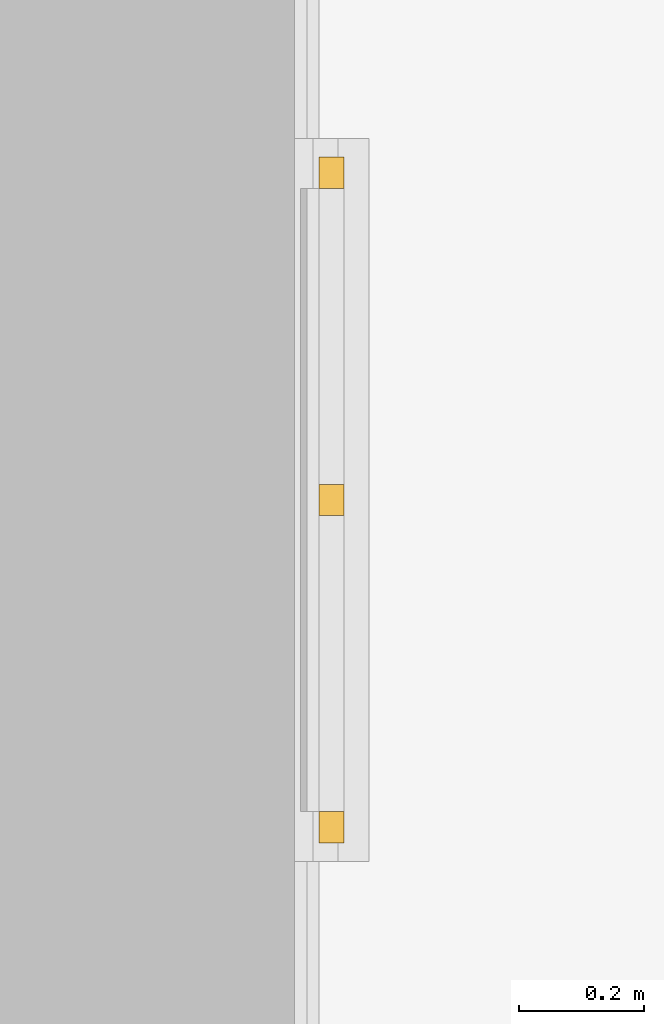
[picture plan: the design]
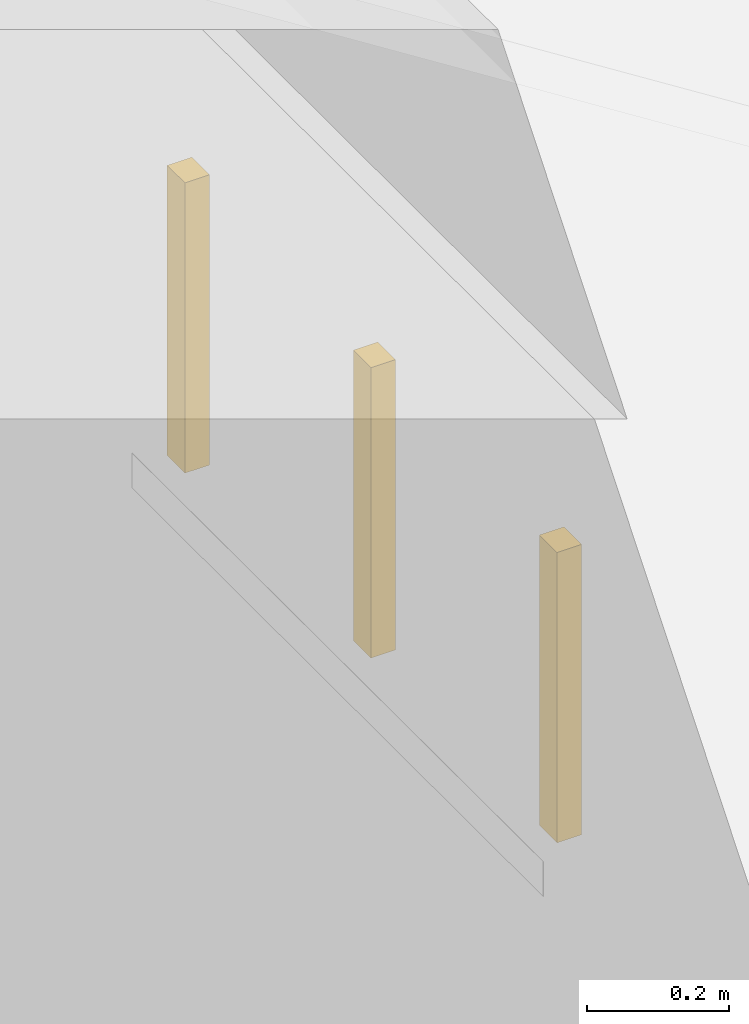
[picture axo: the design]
# One storey, part 86 of 151: 3 windows.
"""IFC2X3 building model written with IfcOpenShell, lengths in metres."""

from ifc_helpers import new_model, si_unit, origin, origin_with_axes, place, context, subcontext, project, spatial, faceted_brep, element, save


model = new_model("IFC2X3")

# Units and contexts
model_context = context("Model", 3, precision=1e-05, world=origin_with_axes())
body_context = subcontext(model_context, "Body", "Model", "MODEL_VIEW")
ifc_project = project(units=[si_unit("LENGTHUNIT", "METRE"), si_unit("AREAUNIT", "SQUARE_METRE"), si_unit("VOLUMEUNIT", "CUBIC_METRE"), si_unit("PLANEANGLEUNIT", "RADIAN")], contexts=[model_context])

# Site, building, storey
site_placement = place(None, origin_with_axes())
site = spatial("IfcSite", under=ifc_project, at=site_placement, CompositionType="ELEMENT")
building_placement = place(site_placement, origin())
building = spatial("IfcBuilding", under=site, at=building_placement, Name="de Temporal", CompositionType="ELEMENT")
storey_placement = place(building_placement, origin())
storey = spatial("IfcBuildingStorey", under=building, at=storey_placement, Name="NIVEL 1 (NPT +0.00)", CompositionType="ELEMENT", Elevation=0.0)

# Windows
window_1_placement = place(storey_placement, origin())
element("IfcWindow", 1, at=window_1_placement, inside=storey, ObjectType="Ventana", context=body_context, shape_type="Brep", body=[
    faceted_brep([(66.54, 118.475, 2.45), (66.54, 118.525, 2.45), (66.58, 118.525, 2.45), (66.58, 118.475, 2.45), (66.54, 118.475, 2.95), (66.58, 118.475, 2.95), (66.58, 118.525, 2.95), (66.54, 118.525, 2.95)], [[[0, 1, 2, 3]], [[4, 5, 6, 7]], [[0, 3, 5, 4]], [[3, 2, 6, 5]], [[2, 1, 7, 6]], [[1, 0, 4, 7]]]),
])
window_2_placement = place(storey_placement, origin())
element("IfcWindow", 2, at=window_2_placement, inside=storey, ObjectType="Ventana", context=body_context, shape_type="Brep", body=[
    faceted_brep([(66.54, 119.525, 2.45), (66.54, 119.575, 2.45), (66.58, 119.575, 2.45), (66.58, 119.525, 2.45), (66.54, 119.525, 2.95), (66.58, 119.525, 2.95), (66.58, 119.575, 2.95), (66.54, 119.575, 2.95)], [[[0, 1, 2, 3]], [[4, 5, 6, 7]], [[0, 3, 5, 4]], [[3, 2, 6, 5]], [[2, 1, 7, 6]], [[1, 0, 4, 7]]]),
])
window_3_placement = place(storey_placement, origin())
element("IfcWindow", 3, at=window_3_placement, inside=storey, ObjectType="Ventana", context=body_context, shape_type="Brep", body=[
    faceted_brep([(66.54, 119.0, 2.45), (66.54, 119.05, 2.45), (66.58, 119.05, 2.45), (66.58, 119.0, 2.45), (66.54, 119.0, 2.95), (66.58, 119.0, 2.95), (66.58, 119.05, 2.95), (66.54, 119.05, 2.95)], [[[0, 1, 2, 3]], [[4, 5, 6, 7]], [[0, 3, 5, 4]], [[3, 2, 6, 5]], [[2, 1, 7, 6]], [[1, 0, 4, 7]]]),
])

save(model, "model.ifc")
